VERSION 5.7 ;
BUSBITCHARS "[]" ;
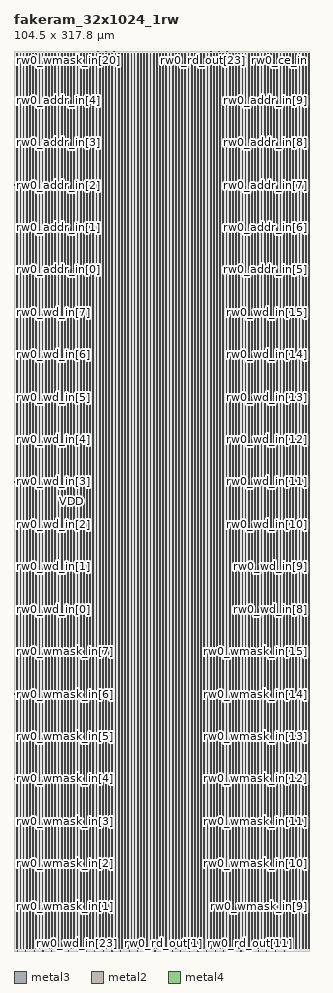
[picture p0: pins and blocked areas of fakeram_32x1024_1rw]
MACRO fakeram_32x1024_1rw
  FOREIGN fakeram_32x1024_1rw 0 0 ;
  SYMMETRY X Y R90 ;
  SIZE 104.500 BY 317.800 ;
  CLASS BLOCK ;
  PIN rw0_wmask_in[0]
    DIRECTION INPUT ;
    USE SIGNAL ;
    SHAPE ABUTMENT ;
    PORT
      LAYER metal3 ;
      RECT 0.000 0.805 0.210 0.875 ;
    END
  END rw0_wmask_in[0]
  PIN rw0_wmask_in[1]
    DIRECTION INPUT ;
    USE SIGNAL ;
    SHAPE ABUTMENT ;
    PORT
      LAYER metal3 ;
      RECT 0.000 15.785 0.210 15.855 ;
    END
  END rw0_wmask_in[1]
  PIN rw0_wmask_in[2]
    DIRECTION INPUT ;
    USE SIGNAL ;
    SHAPE ABUTMENT ;
    PORT
      LAYER metal3 ;
      RECT 0.000 30.765 0.210 30.835 ;
    END
  END rw0_wmask_in[2]
  PIN rw0_wmask_in[3]
    DIRECTION INPUT ;
    USE SIGNAL ;
    SHAPE ABUTMENT ;
    PORT
      LAYER metal3 ;
      RECT 0.000 45.745 0.210 45.815 ;
    END
  END rw0_wmask_in[3]
  PIN rw0_wmask_in[4]
    DIRECTION INPUT ;
    USE SIGNAL ;
    SHAPE ABUTMENT ;
    PORT
      LAYER metal3 ;
      RECT 0.000 60.725 0.210 60.795 ;
    END
  END rw0_wmask_in[4]
  PIN rw0_wmask_in[5]
    DIRECTION INPUT ;
    USE SIGNAL ;
    SHAPE ABUTMENT ;
    PORT
      LAYER metal3 ;
      RECT 0.000 75.705 0.210 75.775 ;
    END
  END rw0_wmask_in[5]
  PIN rw0_wmask_in[6]
    DIRECTION INPUT ;
    USE SIGNAL ;
    SHAPE ABUTMENT ;
    PORT
      LAYER metal3 ;
      RECT 0.000 90.685 0.210 90.755 ;
    END
  END rw0_wmask_in[6]
  PIN rw0_wmask_in[7]
    DIRECTION INPUT ;
    USE SIGNAL ;
    SHAPE ABUTMENT ;
    PORT
      LAYER metal3 ;
      RECT 0.000 105.665 0.210 105.735 ;
    END
  END rw0_wmask_in[7]
  PIN rw0_wmask_in[8]
    DIRECTION INPUT ;
    USE SIGNAL ;
    SHAPE ABUTMENT ;
    PORT
      LAYER metal3 ;
      RECT 104.290 0.805 104.500 0.875 ;
    END
  END rw0_wmask_in[8]
  PIN rw0_wmask_in[9]
    DIRECTION INPUT ;
    USE SIGNAL ;
    SHAPE ABUTMENT ;
    PORT
      LAYER metal3 ;
      RECT 104.290 15.785 104.500 15.855 ;
    END
  END rw0_wmask_in[9]
  PIN rw0_wmask_in[10]
    DIRECTION INPUT ;
    USE SIGNAL ;
    SHAPE ABUTMENT ;
    PORT
      LAYER metal3 ;
      RECT 104.290 30.765 104.500 30.835 ;
    END
  END rw0_wmask_in[10]
  PIN rw0_wmask_in[11]
    DIRECTION INPUT ;
    USE SIGNAL ;
    SHAPE ABUTMENT ;
    PORT
      LAYER metal3 ;
      RECT 104.290 45.745 104.500 45.815 ;
    END
  END rw0_wmask_in[11]
  PIN rw0_wmask_in[12]
    DIRECTION INPUT ;
    USE SIGNAL ;
    SHAPE ABUTMENT ;
    PORT
      LAYER metal3 ;
      RECT 104.290 60.725 104.500 60.795 ;
    END
  END rw0_wmask_in[12]
  PIN rw0_wmask_in[13]
    DIRECTION INPUT ;
    USE SIGNAL ;
    SHAPE ABUTMENT ;
    PORT
      LAYER metal3 ;
      RECT 104.290 75.705 104.500 75.775 ;
    END
  END rw0_wmask_in[13]
  PIN rw0_wmask_in[14]
    DIRECTION INPUT ;
    USE SIGNAL ;
    SHAPE ABUTMENT ;
    PORT
      LAYER metal3 ;
      RECT 104.290 90.685 104.500 90.755 ;
    END
  END rw0_wmask_in[14]
  PIN rw0_wmask_in[15]
    DIRECTION INPUT ;
    USE SIGNAL ;
    SHAPE ABUTMENT ;
    PORT
      LAYER metal3 ;
      RECT 104.290 105.665 104.500 105.735 ;
    END
  END rw0_wmask_in[15]
  PIN rw0_wmask_in[16]
    DIRECTION INPUT ;
    USE SIGNAL ;
    SHAPE ABUTMENT ;
    PORT
      LAYER metal2 ;
      RECT 1.105 317.590 1.175 317.800 ;
    END
  END rw0_wmask_in[16]
  PIN rw0_wmask_in[17]
    DIRECTION INPUT ;
    USE SIGNAL ;
    SHAPE ABUTMENT ;
    PORT
      LAYER metal2 ;
      RECT 3.955 317.590 4.025 317.800 ;
    END
  END rw0_wmask_in[17]
  PIN rw0_wmask_in[18]
    DIRECTION INPUT ;
    USE SIGNAL ;
    SHAPE ABUTMENT ;
    PORT
      LAYER metal2 ;
      RECT 6.805 317.590 6.875 317.800 ;
    END
  END rw0_wmask_in[18]
  PIN rw0_wmask_in[19]
    DIRECTION INPUT ;
    USE SIGNAL ;
    SHAPE ABUTMENT ;
    PORT
      LAYER metal2 ;
      RECT 9.655 317.590 9.725 317.800 ;
    END
  END rw0_wmask_in[19]
  PIN rw0_wmask_in[20]
    DIRECTION INPUT ;
    USE SIGNAL ;
    SHAPE ABUTMENT ;
    PORT
      LAYER metal2 ;
      RECT 12.505 317.590 12.575 317.800 ;
    END
  END rw0_wmask_in[20]
  PIN rw0_wmask_in[21]
    DIRECTION INPUT ;
    USE SIGNAL ;
    SHAPE ABUTMENT ;
    PORT
      LAYER metal2 ;
      RECT 15.355 317.590 15.425 317.800 ;
    END
  END rw0_wmask_in[21]
  PIN rw0_wmask_in[22]
    DIRECTION INPUT ;
    USE SIGNAL ;
    SHAPE ABUTMENT ;
    PORT
      LAYER metal2 ;
      RECT 18.205 317.590 18.275 317.800 ;
    END
  END rw0_wmask_in[22]
  PIN rw0_wmask_in[23]
    DIRECTION INPUT ;
    USE SIGNAL ;
    SHAPE ABUTMENT ;
    PORT
      LAYER metal2 ;
      RECT 21.055 317.590 21.125 317.800 ;
    END
  END rw0_wmask_in[23]
  PIN rw0_wmask_in[24]
    DIRECTION INPUT ;
    USE SIGNAL ;
    SHAPE ABUTMENT ;
    PORT
      LAYER metal2 ;
      RECT 23.905 317.590 23.975 317.800 ;
    END
  END rw0_wmask_in[24]
  PIN rw0_wmask_in[25]
    DIRECTION INPUT ;
    USE SIGNAL ;
    SHAPE ABUTMENT ;
    PORT
      LAYER metal2 ;
      RECT 26.755 317.590 26.825 317.800 ;
    END
  END rw0_wmask_in[25]
  PIN rw0_wmask_in[26]
    DIRECTION INPUT ;
    USE SIGNAL ;
    SHAPE ABUTMENT ;
    PORT
      LAYER metal2 ;
      RECT 29.605 317.590 29.675 317.800 ;
    END
  END rw0_wmask_in[26]
  PIN rw0_wmask_in[27]
    DIRECTION INPUT ;
    USE SIGNAL ;
    SHAPE ABUTMENT ;
    PORT
      LAYER metal2 ;
      RECT 32.455 317.590 32.525 317.800 ;
    END
  END rw0_wmask_in[27]
  PIN rw0_wmask_in[28]
    DIRECTION INPUT ;
    USE SIGNAL ;
    SHAPE ABUTMENT ;
    PORT
      LAYER metal2 ;
      RECT 35.305 317.590 35.375 317.800 ;
    END
  END rw0_wmask_in[28]
  PIN rw0_wmask_in[29]
    DIRECTION INPUT ;
    USE SIGNAL ;
    SHAPE ABUTMENT ;
    PORT
      LAYER metal2 ;
      RECT 38.155 317.590 38.225 317.800 ;
    END
  END rw0_wmask_in[29]
  PIN rw0_wmask_in[30]
    DIRECTION INPUT ;
    USE SIGNAL ;
    SHAPE ABUTMENT ;
    PORT
      LAYER metal2 ;
      RECT 41.005 317.590 41.075 317.800 ;
    END
  END rw0_wmask_in[30]
  PIN rw0_wmask_in[31]
    DIRECTION INPUT ;
    USE SIGNAL ;
    SHAPE ABUTMENT ;
    PORT
      LAYER metal2 ;
      RECT 43.855 317.590 43.925 317.800 ;
    END
  END rw0_wmask_in[31]
  PIN rw0_wd_in[0]
    DIRECTION INPUT ;
    USE SIGNAL ;
    SHAPE ABUTMENT ;
    PORT
      LAYER metal3 ;
      RECT 0.000 120.645 0.210 120.715 ;
    END
  END rw0_wd_in[0]
  PIN rw0_wd_in[1]
    DIRECTION INPUT ;
    USE SIGNAL ;
    SHAPE ABUTMENT ;
    PORT
      LAYER metal3 ;
      RECT 0.000 135.625 0.210 135.695 ;
    END
  END rw0_wd_in[1]
  PIN rw0_wd_in[2]
    DIRECTION INPUT ;
    USE SIGNAL ;
    SHAPE ABUTMENT ;
    PORT
      LAYER metal3 ;
      RECT 0.000 150.605 0.210 150.675 ;
    END
  END rw0_wd_in[2]
  PIN rw0_wd_in[3]
    DIRECTION INPUT ;
    USE SIGNAL ;
    SHAPE ABUTMENT ;
    PORT
      LAYER metal3 ;
      RECT 0.000 165.585 0.210 165.655 ;
    END
  END rw0_wd_in[3]
  PIN rw0_wd_in[4]
    DIRECTION INPUT ;
    USE SIGNAL ;
    SHAPE ABUTMENT ;
    PORT
      LAYER metal3 ;
      RECT 0.000 180.565 0.210 180.635 ;
    END
  END rw0_wd_in[4]
  PIN rw0_wd_in[5]
    DIRECTION INPUT ;
    USE SIGNAL ;
    SHAPE ABUTMENT ;
    PORT
      LAYER metal3 ;
      RECT 0.000 195.545 0.210 195.615 ;
    END
  END rw0_wd_in[5]
  PIN rw0_wd_in[6]
    DIRECTION INPUT ;
    USE SIGNAL ;
    SHAPE ABUTMENT ;
    PORT
      LAYER metal3 ;
      RECT 0.000 210.525 0.210 210.595 ;
    END
  END rw0_wd_in[6]
  PIN rw0_wd_in[7]
    DIRECTION INPUT ;
    USE SIGNAL ;
    SHAPE ABUTMENT ;
    PORT
      LAYER metal3 ;
      RECT 0.000 225.505 0.210 225.575 ;
    END
  END rw0_wd_in[7]
  PIN rw0_wd_in[8]
    DIRECTION INPUT ;
    USE SIGNAL ;
    SHAPE ABUTMENT ;
    PORT
      LAYER metal3 ;
      RECT 104.290 120.645 104.500 120.715 ;
    END
  END rw0_wd_in[8]
  PIN rw0_wd_in[9]
    DIRECTION INPUT ;
    USE SIGNAL ;
    SHAPE ABUTMENT ;
    PORT
      LAYER metal3 ;
      RECT 104.290 135.625 104.500 135.695 ;
    END
  END rw0_wd_in[9]
  PIN rw0_wd_in[10]
    DIRECTION INPUT ;
    USE SIGNAL ;
    SHAPE ABUTMENT ;
    PORT
      LAYER metal3 ;
      RECT 104.290 150.605 104.500 150.675 ;
    END
  END rw0_wd_in[10]
  PIN rw0_wd_in[11]
    DIRECTION INPUT ;
    USE SIGNAL ;
    SHAPE ABUTMENT ;
    PORT
      LAYER metal3 ;
      RECT 104.290 165.585 104.500 165.655 ;
    END
  END rw0_wd_in[11]
  PIN rw0_wd_in[12]
    DIRECTION INPUT ;
    USE SIGNAL ;
    SHAPE ABUTMENT ;
    PORT
      LAYER metal3 ;
      RECT 104.290 180.565 104.500 180.635 ;
    END
  END rw0_wd_in[12]
  PIN rw0_wd_in[13]
    DIRECTION INPUT ;
    USE SIGNAL ;
    SHAPE ABUTMENT ;
    PORT
      LAYER metal3 ;
      RECT 104.290 195.545 104.500 195.615 ;
    END
  END rw0_wd_in[13]
  PIN rw0_wd_in[14]
    DIRECTION INPUT ;
    USE SIGNAL ;
    SHAPE ABUTMENT ;
    PORT
      LAYER metal3 ;
      RECT 104.290 210.525 104.500 210.595 ;
    END
  END rw0_wd_in[14]
  PIN rw0_wd_in[15]
    DIRECTION INPUT ;
    USE SIGNAL ;
    SHAPE ABUTMENT ;
    PORT
      LAYER metal3 ;
      RECT 104.290 225.505 104.500 225.575 ;
    END
  END rw0_wd_in[15]
  PIN rw0_wd_in[16]
    DIRECTION INPUT ;
    USE SIGNAL ;
    SHAPE ABUTMENT ;
    PORT
      LAYER metal2 ;
      RECT 1.105 0.000 1.175 0.210 ;
    END
  END rw0_wd_in[16]
  PIN rw0_wd_in[17]
    DIRECTION INPUT ;
    USE SIGNAL ;
    SHAPE ABUTMENT ;
    PORT
      LAYER metal2 ;
      RECT 4.145 0.000 4.215 0.210 ;
    END
  END rw0_wd_in[17]
  PIN rw0_wd_in[18]
    DIRECTION INPUT ;
    USE SIGNAL ;
    SHAPE ABUTMENT ;
    PORT
      LAYER metal2 ;
      RECT 7.185 0.000 7.255 0.210 ;
    END
  END rw0_wd_in[18]
  PIN rw0_wd_in[19]
    DIRECTION INPUT ;
    USE SIGNAL ;
    SHAPE ABUTMENT ;
    PORT
      LAYER metal2 ;
      RECT 10.225 0.000 10.295 0.210 ;
    END
  END rw0_wd_in[19]
  PIN rw0_wd_in[20]
    DIRECTION INPUT ;
    USE SIGNAL ;
    SHAPE ABUTMENT ;
    PORT
      LAYER metal2 ;
      RECT 13.265 0.000 13.335 0.210 ;
    END
  END rw0_wd_in[20]
  PIN rw0_wd_in[21]
    DIRECTION INPUT ;
    USE SIGNAL ;
    SHAPE ABUTMENT ;
    PORT
      LAYER metal2 ;
      RECT 16.305 0.000 16.375 0.210 ;
    END
  END rw0_wd_in[21]
  PIN rw0_wd_in[22]
    DIRECTION INPUT ;
    USE SIGNAL ;
    SHAPE ABUTMENT ;
    PORT
      LAYER metal2 ;
      RECT 19.345 0.000 19.415 0.210 ;
    END
  END rw0_wd_in[22]
  PIN rw0_wd_in[23]
    DIRECTION INPUT ;
    USE SIGNAL ;
    SHAPE ABUTMENT ;
    PORT
      LAYER metal2 ;
      RECT 22.385 0.000 22.455 0.210 ;
    END
  END rw0_wd_in[23]
  PIN rw0_wd_in[24]
    DIRECTION INPUT ;
    USE SIGNAL ;
    SHAPE ABUTMENT ;
    PORT
      LAYER metal2 ;
      RECT 25.425 0.000 25.495 0.210 ;
    END
  END rw0_wd_in[24]
  PIN rw0_wd_in[25]
    DIRECTION INPUT ;
    USE SIGNAL ;
    SHAPE ABUTMENT ;
    PORT
      LAYER metal2 ;
      RECT 28.465 0.000 28.535 0.210 ;
    END
  END rw0_wd_in[25]
  PIN rw0_wd_in[26]
    DIRECTION INPUT ;
    USE SIGNAL ;
    SHAPE ABUTMENT ;
    PORT
      LAYER metal2 ;
      RECT 31.505 0.000 31.575 0.210 ;
    END
  END rw0_wd_in[26]
  PIN rw0_wd_in[27]
    DIRECTION INPUT ;
    USE SIGNAL ;
    SHAPE ABUTMENT ;
    PORT
      LAYER metal2 ;
      RECT 34.545 0.000 34.615 0.210 ;
    END
  END rw0_wd_in[27]
  PIN rw0_wd_in[28]
    DIRECTION INPUT ;
    USE SIGNAL ;
    SHAPE ABUTMENT ;
    PORT
      LAYER metal2 ;
      RECT 37.585 0.000 37.655 0.210 ;
    END
  END rw0_wd_in[28]
  PIN rw0_wd_in[29]
    DIRECTION INPUT ;
    USE SIGNAL ;
    SHAPE ABUTMENT ;
    PORT
      LAYER metal2 ;
      RECT 40.625 0.000 40.695 0.210 ;
    END
  END rw0_wd_in[29]
  PIN rw0_wd_in[30]
    DIRECTION INPUT ;
    USE SIGNAL ;
    SHAPE ABUTMENT ;
    PORT
      LAYER metal2 ;
      RECT 43.665 0.000 43.735 0.210 ;
    END
  END rw0_wd_in[30]
  PIN rw0_wd_in[31]
    DIRECTION INPUT ;
    USE SIGNAL ;
    SHAPE ABUTMENT ;
    PORT
      LAYER metal2 ;
      RECT 46.705 0.000 46.775 0.210 ;
    END
  END rw0_wd_in[31]
  PIN rw0_rd_out[0]
    DIRECTION OUTPUT ;
    USE SIGNAL ;
    SHAPE ABUTMENT ;
    PORT
      LAYER metal2 ;
      RECT 49.745 0.000 49.815 0.210 ;
    END
  END rw0_rd_out[0]
  PIN rw0_rd_out[1]
    DIRECTION OUTPUT ;
    USE SIGNAL ;
    SHAPE ABUTMENT ;
    PORT
      LAYER metal2 ;
      RECT 52.785 0.000 52.855 0.210 ;
    END
  END rw0_rd_out[1]
  PIN rw0_rd_out[2]
    DIRECTION OUTPUT ;
    USE SIGNAL ;
    SHAPE ABUTMENT ;
    PORT
      LAYER metal2 ;
      RECT 55.825 0.000 55.895 0.210 ;
    END
  END rw0_rd_out[2]
  PIN rw0_rd_out[3]
    DIRECTION OUTPUT ;
    USE SIGNAL ;
    SHAPE ABUTMENT ;
    PORT
      LAYER metal2 ;
      RECT 58.865 0.000 58.935 0.210 ;
    END
  END rw0_rd_out[3]
  PIN rw0_rd_out[4]
    DIRECTION OUTPUT ;
    USE SIGNAL ;
    SHAPE ABUTMENT ;
    PORT
      LAYER metal2 ;
      RECT 61.905 0.000 61.975 0.210 ;
    END
  END rw0_rd_out[4]
  PIN rw0_rd_out[5]
    DIRECTION OUTPUT ;
    USE SIGNAL ;
    SHAPE ABUTMENT ;
    PORT
      LAYER metal2 ;
      RECT 64.945 0.000 65.015 0.210 ;
    END
  END rw0_rd_out[5]
  PIN rw0_rd_out[6]
    DIRECTION OUTPUT ;
    USE SIGNAL ;
    SHAPE ABUTMENT ;
    PORT
      LAYER metal2 ;
      RECT 67.985 0.000 68.055 0.210 ;
    END
  END rw0_rd_out[6]
  PIN rw0_rd_out[7]
    DIRECTION OUTPUT ;
    USE SIGNAL ;
    SHAPE ABUTMENT ;
    PORT
      LAYER metal2 ;
      RECT 71.025 0.000 71.095 0.210 ;
    END
  END rw0_rd_out[7]
  PIN rw0_rd_out[8]
    DIRECTION OUTPUT ;
    USE SIGNAL ;
    SHAPE ABUTMENT ;
    PORT
      LAYER metal2 ;
      RECT 74.065 0.000 74.135 0.210 ;
    END
  END rw0_rd_out[8]
  PIN rw0_rd_out[9]
    DIRECTION OUTPUT ;
    USE SIGNAL ;
    SHAPE ABUTMENT ;
    PORT
      LAYER metal2 ;
      RECT 77.105 0.000 77.175 0.210 ;
    END
  END rw0_rd_out[9]
  PIN rw0_rd_out[10]
    DIRECTION OUTPUT ;
    USE SIGNAL ;
    SHAPE ABUTMENT ;
    PORT
      LAYER metal2 ;
      RECT 80.145 0.000 80.215 0.210 ;
    END
  END rw0_rd_out[10]
  PIN rw0_rd_out[11]
    DIRECTION OUTPUT ;
    USE SIGNAL ;
    SHAPE ABUTMENT ;
    PORT
      LAYER metal2 ;
      RECT 83.185 0.000 83.255 0.210 ;
    END
  END rw0_rd_out[11]
  PIN rw0_rd_out[12]
    DIRECTION OUTPUT ;
    USE SIGNAL ;
    SHAPE ABUTMENT ;
    PORT
      LAYER metal2 ;
      RECT 86.225 0.000 86.295 0.210 ;
    END
  END rw0_rd_out[12]
  PIN rw0_rd_out[13]
    DIRECTION OUTPUT ;
    USE SIGNAL ;
    SHAPE ABUTMENT ;
    PORT
      LAYER metal2 ;
      RECT 89.265 0.000 89.335 0.210 ;
    END
  END rw0_rd_out[13]
  PIN rw0_rd_out[14]
    DIRECTION OUTPUT ;
    USE SIGNAL ;
    SHAPE ABUTMENT ;
    PORT
      LAYER metal2 ;
      RECT 92.305 0.000 92.375 0.210 ;
    END
  END rw0_rd_out[14]
  PIN rw0_rd_out[15]
    DIRECTION OUTPUT ;
    USE SIGNAL ;
    SHAPE ABUTMENT ;
    PORT
      LAYER metal2 ;
      RECT 95.345 0.000 95.415 0.210 ;
    END
  END rw0_rd_out[15]
  PIN rw0_rd_out[16]
    DIRECTION OUTPUT ;
    USE SIGNAL ;
    SHAPE ABUTMENT ;
    PORT
      LAYER metal2 ;
      RECT 46.705 317.590 46.775 317.800 ;
    END
  END rw0_rd_out[16]
  PIN rw0_rd_out[17]
    DIRECTION OUTPUT ;
    USE SIGNAL ;
    SHAPE ABUTMENT ;
    PORT
      LAYER metal2 ;
      RECT 49.555 317.590 49.625 317.800 ;
    END
  END rw0_rd_out[17]
  PIN rw0_rd_out[18]
    DIRECTION OUTPUT ;
    USE SIGNAL ;
    SHAPE ABUTMENT ;
    PORT
      LAYER metal2 ;
      RECT 52.405 317.590 52.475 317.800 ;
    END
  END rw0_rd_out[18]
  PIN rw0_rd_out[19]
    DIRECTION OUTPUT ;
    USE SIGNAL ;
    SHAPE ABUTMENT ;
    PORT
      LAYER metal2 ;
      RECT 55.255 317.590 55.325 317.800 ;
    END
  END rw0_rd_out[19]
  PIN rw0_rd_out[20]
    DIRECTION OUTPUT ;
    USE SIGNAL ;
    SHAPE ABUTMENT ;
    PORT
      LAYER metal2 ;
      RECT 58.105 317.590 58.175 317.800 ;
    END
  END rw0_rd_out[20]
  PIN rw0_rd_out[21]
    DIRECTION OUTPUT ;
    USE SIGNAL ;
    SHAPE ABUTMENT ;
    PORT
      LAYER metal2 ;
      RECT 60.955 317.590 61.025 317.800 ;
    END
  END rw0_rd_out[21]
  PIN rw0_rd_out[22]
    DIRECTION OUTPUT ;
    USE SIGNAL ;
    SHAPE ABUTMENT ;
    PORT
      LAYER metal2 ;
      RECT 63.805 317.590 63.875 317.800 ;
    END
  END rw0_rd_out[22]
  PIN rw0_rd_out[23]
    DIRECTION OUTPUT ;
    USE SIGNAL ;
    SHAPE ABUTMENT ;
    PORT
      LAYER metal2 ;
      RECT 66.655 317.590 66.725 317.800 ;
    END
  END rw0_rd_out[23]
  PIN rw0_rd_out[24]
    DIRECTION OUTPUT ;
    USE SIGNAL ;
    SHAPE ABUTMENT ;
    PORT
      LAYER metal2 ;
      RECT 69.505 317.590 69.575 317.800 ;
    END
  END rw0_rd_out[24]
  PIN rw0_rd_out[25]
    DIRECTION OUTPUT ;
    USE SIGNAL ;
    SHAPE ABUTMENT ;
    PORT
      LAYER metal2 ;
      RECT 72.355 317.590 72.425 317.800 ;
    END
  END rw0_rd_out[25]
  PIN rw0_rd_out[26]
    DIRECTION OUTPUT ;
    USE SIGNAL ;
    SHAPE ABUTMENT ;
    PORT
      LAYER metal2 ;
      RECT 75.205 317.590 75.275 317.800 ;
    END
  END rw0_rd_out[26]
  PIN rw0_rd_out[27]
    DIRECTION OUTPUT ;
    USE SIGNAL ;
    SHAPE ABUTMENT ;
    PORT
      LAYER metal2 ;
      RECT 78.055 317.590 78.125 317.800 ;
    END
  END rw0_rd_out[27]
  PIN rw0_rd_out[28]
    DIRECTION OUTPUT ;
    USE SIGNAL ;
    SHAPE ABUTMENT ;
    PORT
      LAYER metal2 ;
      RECT 80.905 317.590 80.975 317.800 ;
    END
  END rw0_rd_out[28]
  PIN rw0_rd_out[29]
    DIRECTION OUTPUT ;
    USE SIGNAL ;
    SHAPE ABUTMENT ;
    PORT
      LAYER metal2 ;
      RECT 83.755 317.590 83.825 317.800 ;
    END
  END rw0_rd_out[29]
  PIN rw0_rd_out[30]
    DIRECTION OUTPUT ;
    USE SIGNAL ;
    SHAPE ABUTMENT ;
    PORT
      LAYER metal2 ;
      RECT 86.605 317.590 86.675 317.800 ;
    END
  END rw0_rd_out[30]
  PIN rw0_rd_out[31]
    DIRECTION OUTPUT ;
    USE SIGNAL ;
    SHAPE ABUTMENT ;
    PORT
      LAYER metal2 ;
      RECT 89.455 317.590 89.525 317.800 ;
    END
  END rw0_rd_out[31]
  PIN rw0_addr_in[0]
    DIRECTION INPUT ;
    USE SIGNAL ;
    SHAPE ABUTMENT ;
    PORT
      LAYER metal3 ;
      RECT 0.000 240.485 0.210 240.555 ;
    END
  END rw0_addr_in[0]
  PIN rw0_addr_in[1]
    DIRECTION INPUT ;
    USE SIGNAL ;
    SHAPE ABUTMENT ;
    PORT
      LAYER metal3 ;
      RECT 0.000 255.465 0.210 255.535 ;
    END
  END rw0_addr_in[1]
  PIN rw0_addr_in[2]
    DIRECTION INPUT ;
    USE SIGNAL ;
    SHAPE ABUTMENT ;
    PORT
      LAYER metal3 ;
      RECT 0.000 270.445 0.210 270.515 ;
    END
  END rw0_addr_in[2]
  PIN rw0_addr_in[3]
    DIRECTION INPUT ;
    USE SIGNAL ;
    SHAPE ABUTMENT ;
    PORT
      LAYER metal3 ;
      RECT 0.000 285.425 0.210 285.495 ;
    END
  END rw0_addr_in[3]
  PIN rw0_addr_in[4]
    DIRECTION INPUT ;
    USE SIGNAL ;
    SHAPE ABUTMENT ;
    PORT
      LAYER metal3 ;
      RECT 0.000 300.405 0.210 300.475 ;
    END
  END rw0_addr_in[4]
  PIN rw0_addr_in[5]
    DIRECTION INPUT ;
    USE SIGNAL ;
    SHAPE ABUTMENT ;
    PORT
      LAYER metal3 ;
      RECT 104.290 240.485 104.500 240.555 ;
    END
  END rw0_addr_in[5]
  PIN rw0_addr_in[6]
    DIRECTION INPUT ;
    USE SIGNAL ;
    SHAPE ABUTMENT ;
    PORT
      LAYER metal3 ;
      RECT 104.290 255.465 104.500 255.535 ;
    END
  END rw0_addr_in[6]
  PIN rw0_addr_in[7]
    DIRECTION INPUT ;
    USE SIGNAL ;
    SHAPE ABUTMENT ;
    PORT
      LAYER metal3 ;
      RECT 104.290 270.445 104.500 270.515 ;
    END
  END rw0_addr_in[7]
  PIN rw0_addr_in[8]
    DIRECTION INPUT ;
    USE SIGNAL ;
    SHAPE ABUTMENT ;
    PORT
      LAYER metal3 ;
      RECT 104.290 285.425 104.500 285.495 ;
    END
  END rw0_addr_in[8]
  PIN rw0_addr_in[9]
    DIRECTION INPUT ;
    USE SIGNAL ;
    SHAPE ABUTMENT ;
    PORT
      LAYER metal3 ;
      RECT 104.290 300.405 104.500 300.475 ;
    END
  END rw0_addr_in[9]
  PIN rw0_we_in
    DIRECTION INPUT ;
    USE SIGNAL ;
    SHAPE ABUTMENT ;
    PORT
      LAYER metal2 ;
      RECT 92.305 317.590 92.375 317.800 ;
    END
  END rw0_we_in
  PIN rw0_ce_in
    DIRECTION INPUT ;
    USE SIGNAL ;
    SHAPE ABUTMENT ;
    PORT
      LAYER metal2 ;
      RECT 95.155 317.590 95.225 317.800 ;
    END
  END rw0_ce_in
  PIN rw0_clk
    DIRECTION INPUT ;
    USE SIGNAL ;
    SHAPE ABUTMENT ;
    PORT
      LAYER metal2 ;
      RECT 98.005 317.590 98.075 317.800 ;
    END
  END rw0_clk
  PIN VSS
    DIRECTION INOUT ;
    USE GROUND ;
    PORT
      LAYER metal4 ;
      RECT 1.000 0.840 1.280 316.960 ;
      RECT 3.240 0.840 3.520 316.960 ;
      RECT 5.480 0.840 5.760 316.960 ;
      RECT 7.720 0.840 8.000 316.960 ;
      RECT 9.960 0.840 10.240 316.960 ;
      RECT 12.200 0.840 12.480 316.960 ;
      RECT 14.440 0.840 14.720 316.960 ;
      RECT 16.680 0.840 16.960 316.960 ;
      RECT 18.920 0.840 19.200 316.960 ;
      RECT 21.160 0.840 21.440 316.960 ;
      RECT 23.400 0.840 23.680 316.960 ;
      RECT 25.640 0.840 25.920 316.960 ;
      RECT 27.880 0.840 28.160 316.960 ;
      RECT 30.120 0.840 30.400 316.960 ;
      RECT 32.360 0.840 32.640 316.960 ;
      RECT 34.600 0.840 34.880 316.960 ;
      RECT 36.840 0.840 37.120 316.960 ;
      RECT 39.080 0.840 39.360 316.960 ;
      RECT 41.320 0.840 41.600 316.960 ;
      RECT 43.560 0.840 43.840 316.960 ;
      RECT 45.800 0.840 46.080 316.960 ;
      RECT 48.040 0.840 48.320 316.960 ;
      RECT 50.280 0.840 50.560 316.960 ;
      RECT 52.520 0.840 52.800 316.960 ;
      RECT 54.760 0.840 55.040 316.960 ;
      RECT 57.000 0.840 57.280 316.960 ;
      RECT 59.240 0.840 59.520 316.960 ;
      RECT 61.480 0.840 61.760 316.960 ;
      RECT 63.720 0.840 64.000 316.960 ;
      RECT 65.960 0.840 66.240 316.960 ;
      RECT 68.200 0.840 68.480 316.960 ;
      RECT 70.440 0.840 70.720 316.960 ;
      RECT 72.680 0.840 72.960 316.960 ;
      RECT 74.920 0.840 75.200 316.960 ;
      RECT 77.160 0.840 77.440 316.960 ;
      RECT 79.400 0.840 79.680 316.960 ;
      RECT 81.640 0.840 81.920 316.960 ;
      RECT 83.880 0.840 84.160 316.960 ;
      RECT 86.120 0.840 86.400 316.960 ;
      RECT 88.360 0.840 88.640 316.960 ;
      RECT 90.600 0.840 90.880 316.960 ;
      RECT 92.840 0.840 93.120 316.960 ;
      RECT 95.080 0.840 95.360 316.960 ;
      RECT 97.320 0.840 97.600 316.960 ;
      RECT 99.560 0.840 99.840 316.960 ;
      RECT 101.800 0.840 102.080 316.960 ;
      RECT 104.040 0.840 104.320 316.960 ;
    END
  END VSS
  PIN VDD
    DIRECTION INOUT ;
    USE POWER ;
    PORT
      LAYER metal4 ;
      RECT 2.120 0.840 2.400 316.960 ;
      RECT 4.360 0.840 4.640 316.960 ;
      RECT 6.600 0.840 6.880 316.960 ;
      RECT 8.840 0.840 9.120 316.960 ;
      RECT 11.080 0.840 11.360 316.960 ;
      RECT 13.320 0.840 13.600 316.960 ;
      RECT 15.560 0.840 15.840 316.960 ;
      RECT 17.800 0.840 18.080 316.960 ;
      RECT 20.040 0.840 20.320 316.960 ;
      RECT 22.280 0.840 22.560 316.960 ;
      RECT 24.520 0.840 24.800 316.960 ;
      RECT 26.760 0.840 27.040 316.960 ;
      RECT 29.000 0.840 29.280 316.960 ;
      RECT 31.240 0.840 31.520 316.960 ;
      RECT 33.480 0.840 33.760 316.960 ;
      RECT 35.720 0.840 36.000 316.960 ;
      RECT 37.960 0.840 38.240 316.960 ;
      RECT 40.200 0.840 40.480 316.960 ;
      RECT 42.440 0.840 42.720 316.960 ;
      RECT 44.680 0.840 44.960 316.960 ;
      RECT 46.920 0.840 47.200 316.960 ;
      RECT 49.160 0.840 49.440 316.960 ;
      RECT 51.400 0.840 51.680 316.960 ;
      RECT 53.640 0.840 53.920 316.960 ;
      RECT 55.880 0.840 56.160 316.960 ;
      RECT 58.120 0.840 58.400 316.960 ;
      RECT 60.360 0.840 60.640 316.960 ;
      RECT 62.600 0.840 62.880 316.960 ;
      RECT 64.840 0.840 65.120 316.960 ;
      RECT 67.080 0.840 67.360 316.960 ;
      RECT 69.320 0.840 69.600 316.960 ;
      RECT 71.560 0.840 71.840 316.960 ;
      RECT 73.800 0.840 74.080 316.960 ;
      RECT 76.040 0.840 76.320 316.960 ;
      RECT 78.280 0.840 78.560 316.960 ;
      RECT 80.520 0.840 80.800 316.960 ;
      RECT 82.760 0.840 83.040 316.960 ;
      RECT 85.000 0.840 85.280 316.960 ;
      RECT 87.240 0.840 87.520 316.960 ;
      RECT 89.480 0.840 89.760 316.960 ;
      RECT 91.720 0.840 92.000 316.960 ;
      RECT 93.960 0.840 94.240 316.960 ;
      RECT 96.200 0.840 96.480 316.960 ;
      RECT 98.440 0.840 98.720 316.960 ;
      RECT 100.680 0.840 100.960 316.960 ;
      RECT 102.920 0.840 103.200 316.960 ;
    END
  END VDD
  OBS
    LAYER metal1 ;
    RECT 0 0 104.500 317.800 ;
    LAYER metal2 ;
    RECT 0 0 104.500 317.800 ;
    LAYER metal3 ;
    RECT 0 0 104.500 317.800 ;
    LAYER metal4 ;
    RECT 0 0 104.500 317.800 ;
    LAYER OVERLAP ;
    RECT 0 0 104.500 317.800 ;
  END
END fakeram_32x1024_1rw

END LIBRARY
